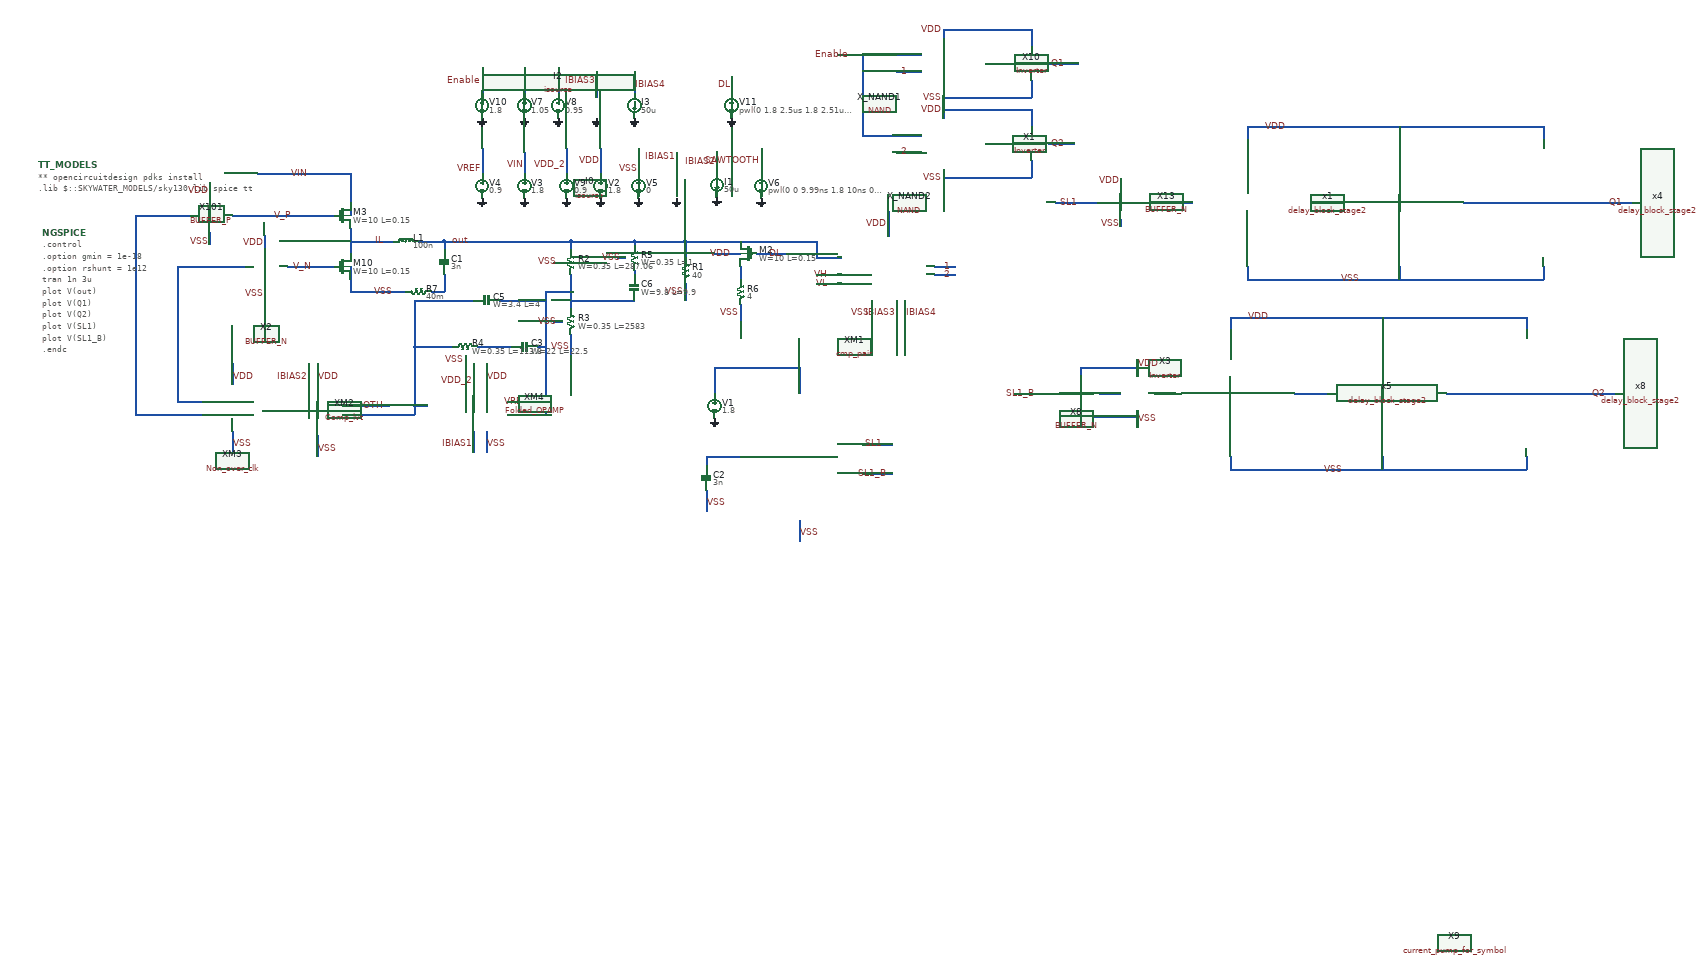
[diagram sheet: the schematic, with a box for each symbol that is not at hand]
v {xschem version=3.0.0 file_version=1.2 }
G {}
K {}
V {}
S {}
E {}
N 470 80 470 140 {
lab=IL}
N 470 20 470 50 {
lab=VIN}
N 380 50 430 50 {
lab=V_P}
N 470 -50 470 20 {
lab=VIN}
N 250 -50 470 -50 {
lab=VIN}
N 470 200 470 230 {
lab=VSS}
N 470 110 530 110 {
lab=IL}
N 530 110 570 110 {
lab=IL}
N 690 110 690 130 {
lab=out}
N 630 110 690 110 {
lab=out}
N 690 190 690 230 {
lab=#net1}
N 690 110 800 110 {
lab=out}
N 790 400 790 450 {
lab=VDD}
N 760 400 760 450 {
lab=VDD_2}
N 790 560 790 610 {
lab=VSS}
N 760 560 760 610 {
lab=IBIAS1}
N 840 520 890 520 {
lab=#net2}
N 840 490 890 490 {
lab=VREF}
N 880 -100 880 -50 {
lab=VIN}
N 980 -110 980 -50 {
lab=VDD_2}
N 1060 -60 1060 -50 {
lab=VDD}
N 1060 -110 1060 -60 {
lab=VDD}
N 1150 -80 1150 -60 {
lab=VSS}
N 1150 -60 1150 -50 {
lab=VSS}
N 1150 -110 1150 -80 {
lab=VSS}
N 1240 -100 1240 -40 {
lab=IBIAS1}
N 390 400 390 450 {
lab=VDD}
N 390 570 390 620 {
lab=VSS}
N 780 -80 780 -60 {
lab=VREF}
N 780 -60 780 -50 {
lab=VREF}
N 780 -110 780 -80 {
lab=VREF}
N 890 520 920 520 {
lab=#net2}
N 370 400 370 450 {
lab=IBIAS2}
N 1440 -110 1440 -50 {
lab=SAWTOOTH}
N 190 50 380 50 {
lab=V_P}
N 800 110 980 110 {
lab=out}
N 990 110 990 130 {
lab=out}
N 990 190 990 240 {
lab=#net2}
N 990 330 990 380 {
lab=VSS}
N 770 360 850 360 {
lab=#net3}
N 620 360 710 360 {
lab=#net4}
N 620 360 620 500 {
lab=#net4}
N 930 360 930 490 {
lab=#net2}
N 910 360 930 360 {
lab=#net2}
N 620 250 760 250 {
lab=#net4}
N 820 250 930 250 {
lab=#net2}
N 930 290 930 360 {
lab=#net2}
N 620 500 650 500 {
lab=#net4}
N 930 490 930 520 {
lab=#net2}
N 920 520 930 520 {
lab=#net2}
N 990 110 1140 110 {
lab=out}
N 1140 110 1140 120 {
lab=out}
N 1140 180 1140 190 {
lab=#net5}
N 980 110 990 110 {
lab=out}
N 930 230 930 290 {
lab=#net2}
N 930 230 990 230 {
lab=#net2}
N 990 240 990 270 {
lab=#net2}
N 1260 110 1260 150 {
lab=out}
N 1140 110 1260 110 {
lab=out}
N 1260 210 1260 250 {
lab=VSS}
N 450 520 620 520 {
lab=#net4}
N 620 500 620 520 {
lab=#net4}
N 380 170 430 170 {
lab=V_N}
N 470 170 470 200 {
lab=VSS}
N 1260 110 1390 110 {
lab=out}
N 1390 260 1390 300 {
lab=VSS}
N 1390 170 1390 200 {
lab=#net6}
N 1430 140 1500 140 {
lab=DL}
N 190 400 190 450 {
lab=VDD}
N 190 560 190 610 {
lab=VSS}
N -40 50 90 50 {
lab=#net7}
N -40 50 -40 490 {
lab=#net7}
N 135 90 135 117.5 {
lab=VSS}
N 135 -27.5 135 7.5 {
lab=VDD}
N 320 170 380 170 {
lab=V_N}
N 60 170 220 170 {
lab=#net8}
N 60 170 60 260 {
lab=#net8}
N 265 210 265 247.5 {
lab=VSS}
N 265 97.5 265 127.5 {
lab=VDD}
N 60 490 120 490 {
lab=#net8}
N 60 260 60 490 {
lab=#net8}
N -40 520 120 520 {
lab=#net7}
N -40 490 -40 520 {
lab=#net7}
N 620 250 620 360 {
lab=#net4}
N 990 250 1040 250 {
lab=#net2}
N 1040 250 1140 250 {
lab=#net2}
N 790 560 790 610 {
lab=VSS}
N 1330 140 1390 140 {
lab=VDD}
N 1335 -102.5 1335 -52.5 {
lab=IBIAS2}
N 270 510 320 510 {
lab=#net9}
N 450 500 560 500 {
lab=SAWTOOTH}
N 740 380 740 400 {
lab=VSS}
N 1100 150 1120 150 {
lab=VSS}
N 950 160 970 160 {
lab=VSS}
N 950 300 970 300 {
lab=VSS}
N 470 230 600 230 {
lab=VSS}
N 660 230 690 230 {
lab=#net1}
N 260 510 270 510 {
lab=#net9}
N 1850 170 1900 170 {
lab=1}
N 1850 190 1900 190 {
lab=2}
N 1780 250 1780 300 {
lab=IBIAS4}
N 1760 250 1760 310 {
lab=IBIAS3}
N 1700 250 1700 310 {
lab=VSS}
N 1740 40 1740 100 {
lab=VDD}
N 1570 150 1630 150 {
lab=out}
N 1570 190 1630 190 {
lab=VH}
N 1570 210 1630 210 {
lab=VL}
N 1570 110 1570 150 {
lab=out}
N 880 -300 880 -240 {
lab=VH}
N 960 -300 960 -240 {
lab=VL}
N 1050 -290 1050 -230 {
lab=IBIAS3}
N 1140 -290 1140 -240 {
lab=IBIAS4}
N 1680 -140 1820 -140 {
lab=Enable}
N 1680 -330 1820 -330 {
lab=Enable}
N 1620 -330 1680 -330 {
lab=Enable}
N 1760 -290 1820 -290 {
lab=1}
N 1760 -100 1820 -100 {
lab=2}
N 2120 -310 2180 -310 {
lab=Q1}
N 2120 -120 2180 -120 {
lab=Q2}
N 2180 -310 2190 -310 {
lab=Q1}
N 780 -300 780 -240 {
lab=Enable}
N 1370 -260 1370 -240 {
lab=DL}
N 1370 -280 1370 -260 {
lab=DL}
N 1390 110 1570 110 {
lab=out}
N 1870 -60 1870 -40 {
lab=VSS}
N 1870 -40 2010 -40 {
lab=VSS}
N 1870 -200 1870 -180 {
lab=VDD}
N 1870 -200 2010 -200 {
lab=VDD}
N 1870 -250 1870 -230 {
lab=VSS}
N 1870 -230 2010 -230 {
lab=VSS}
N 1870 -390 1870 -370 {
lab=VDD}
N 1680 -330 1680 -140 {
lab=Enable}
N 2240 470 2290 470 {
lab=#net10}
N 2330 510 2330 550 {
lab=VSS}
N 2330 390 2330 430 {
lab=VDD}
N 2040 470 2140 470 {
lab=SL1_B}
N 2195 410 2195 427.5 {
lab=VDD}
N 2195 410 2330 410 {
lab=VDD}
N 2195 510 2195 525 {
lab=VSS}
N 2195 525 2330 525 {
lab=VSS}
N 2135 20 2235 20 {
lab=SL1}
N 2290 -37.5 2290 -22.5 {
lab=VDD}
N 2290 60 2290 75 {
lab=VSS}
N 2010 -230 2080 -230 {
lab=VSS}
N 1880 -390 2080 -390 {
lab=VDD}
N 1870 -390 1880 -390 {
lab=VDD}
N 2010 -40 2080 -40 {
lab=VSS}
N 2010 -200 2080 -200 {
lab=VDD}
N 2080 -390 2080 -350 {
lab=VDD}
N 2080 -270 2080 -230 {
lab=VSS}
N 1970 -310 2040 -310 {
lab=#net11}
N 1970 -120 2040 -120 {
lab=#net12}
N 2080 -200 2080 -160 {
lab=VDD}
N 2080 -80 2080 -40 {
lab=VSS}
N 1530 770 1530 820 {
lab=VSS}
N 1530 770 1530 820 {
lab=VSS}
N 1330 420 1330 470 {
lab=#net13}
N 1530 410 1530 470 {
lab=#net13}
N 1330 410 1530 410 {
lab=#net13}
N 1330 410 1330 420 {
lab=#net13}
N 1310 620 1390 620 {
lab=#net14}
N 1310 620 1310 640 {
lab=#net14}
N 1310 700 1310 750 {
lab=VSS}
N 1310 700 1310 750 {
lab=VSS}
N 1680 590 1750 590 {
lab=SL1}
N 1680 660 1750 660 {
lab=SL1_B}
N 2740 20 2780 20 {
lab=#net15}
N 2780 20 2820 20 {
lab=#net15}
N 2590 -160 2590 -130 {
lab=VDD}
N 2950 -160 2950 -130 {
lab=VDD}
N 2950 170 2950 200 {
lab=VSS}
N 2590 170 2590 200 {
lab=VSS}
N 2700 470 2740 470 {
lab=#net16}
N 2740 470 2780 470 {
lab=#net16}
N 2550 290 2550 320 {
lab=VDD}
N 2910 290 2910 320 {
lab=VDD}
N 2910 620 2910 650 {
lab=VSS}
N 2550 620 2550 650 {
lab=VSS}
N 3060 470 3120 470 {
lab=#net17}
N 2370 470 2420 470 {
lab=#net18}
N 2335 20 2460 20 {
lab=#net19}
N 3120 20 3160 20 {
lab=#net20}
N 3290 -160 3290 -130 {
lab=VDD}
N 3290 170 3290 200 {
lab=VSS}
N 3440 20 3500 20 {
lab=Q1}
N 3250 290 3250 320 {
lab=VDD}
N 3250 620 3250 650 {
lab=VSS}
N 3400 470 3460 470 {
lab=Q2}
N 3100 20 3120 20 {
lab=#net20}
N 2550 650 3250 650 {
lab=VSS}
N 2550 290 3250 290 {
lab=VDD}
N 2590 200 3290 200 {
lab=VSS}
N 2590 -160 3290 -160 {
lab=VDD}
N 3120 470 3400 470 {}
N 3160 20 3440 20 {}
C {sky130_fd_pr/pfet_01v8.sym} 450 50 0 0 {name=M3
L=0.15
W=10
nf=1
mult=450
ad="'int((nf+1)/2) * W/nf * 0.29'" 
pd="'2*int((nf+1)/2) * (W/nf + 0.29)'"
as="'int((nf+2)/2) * W/nf * 0.29'" 
ps="'2*int((nf+2)/2) * (W/nf + 0.29)'"
nrd="'0.29 / W'" nrs="'0.29 / W'"
sa=0 sb=0 sd=0
model=pfet_01v8
spiceprefix=X
}
C {devices/ind.sym} 600 110 3 0 {name=L1
m=1
value=100n
footprint=1206
device=inductor}
C {devices/capa.sym} 690 160 0 0 {name=C1
m=1
value=3n
footprint=1206
device="ceramic capacitor"}
C {devices/code.sym} -270 -70 0 0 {name=TT_MODELS
only_toplevel=true
format="tcleval( @value )"
value="
** opencircuitdesign pdks install
.lib $::SKYWATER_MODELS/sky130.lib.spice tt

"
spice_ignore=false}
C {devices/code_shown.sym} -260 90 0 0 {name=NGSPICE
only_toplevel=true
value="

.control

.option gmin = 1e-18
.option rshunt = 1e12
tran 1n 3u
plot V(out)
plot V(Q1)
plot V(Q2) 
plot V(SL1)
plot V(SL1_B)
.endc
" }
C {devices/lab_wire.sym} 750 110 0 0 {name=l4 sig_type=std_logic lab=out}
C {devices/lab_wire.sym} 550 110 0 0 {name=l6 sig_type=std_logic lab=IL}
C {devices/lab_wire.sym} 370 -50 0 0 {name=l5 sig_type=std_logic lab=VIN}
C {devices/vsource.sym} 880 -20 0 0 {name=V3 value=1.8}
C {devices/gnd.sym} 880 10 0 0 {name=l7 lab=GND}
C {devices/lab_wire.sym} 880 -70 0 0 {name=l2 sig_type=std_logic lab=VIN}
C {devices/gnd.sym} 1240 10 0 0 {name=l19 lab=GND}
C {devices/lab_wire.sym} 1240 -90 0 0 {name=l22 sig_type=std_logic lab=IBIAS1}
C {devices/isource.sym} 1240 -20 0 0 {name=I0 value=50u}
C {devices/vsource.sym} 980 -20 0 0 {name=V9 value=0.9}
C {devices/gnd.sym} 980 10 0 0 {name=l42 lab=GND}
C {devices/lab_wire.sym} 980 -70 0 0 {name=l8 sig_type=std_logic lab=VDD_2}
C {devices/vsource.sym} 1060 -20 0 0 {name=V2 value=1.8}
C {devices/gnd.sym} 1060 10 0 0 {name=l18 lab=GND}
C {devices/vsource.sym} 1150 -20 0 0 {name=V5 value=0}
C {devices/gnd.sym} 1150 10 0 0 {name=l26 lab=GND}
C {devices/lab_wire.sym} 1150 -60 0 0 {name=l10 sig_type=std_logic lab=VSS}
C {devices/lab_wire.sym} 790 430 0 1 {name=l13 sig_type=std_logic lab=VDD}
C {devices/lab_wire.sym} 760 440 0 0 {name=l14 sig_type=std_logic lab=VDD_2}
C {devices/lab_wire.sym} 570 230 0 0 {name=l1 sig_type=std_logic lab=VSS}
C {devices/lab_wire.sym} 790 590 0 1 {name=l15 sig_type=std_logic lab=VSS}
C {devices/lab_wire.sym} 760 590 0 0 {name=l16 sig_type=std_logic lab=IBIAS1}
C {devices/lab_wire.sym} 390 430 0 1 {name=l11 sig_type=std_logic lab=VDD}
C {devices/lab_wire.sym} 390 600 0 1 {name=l12 sig_type=std_logic lab=VSS}
C {devices/vsource.sym} 780 -20 0 0 {name=V4 value=0.9}
C {devices/gnd.sym} 780 10 0 0 {name=l17 lab=GND}
C {devices/lab_wire.sym} 780 -60 0 0 {name=l20 sig_type=std_logic lab=VREF}
C {devices/isource.sym} 1335 -22.5 0 1 {name=I1 value=50u}
C {devices/lab_wire.sym} 370 430 0 0 {name=l27 sig_type=std_logic lab=IBIAS2}
C {devices/vsource.sym} 1440 -20 0 0 {name=V6 value="pwl(0 0 9.99ns 1.8 10ns 0) r=0"}
C {devices/gnd.sym} 1440 10 0 0 {name=l28 lab=GND}
C {devices/gnd.sym} 1440 10 0 0 {name=l29 lab=GND}
C {devices/lab_wire.sym} 1440 -80 0 0 {name=l30 sig_type=std_logic lab=SAWTOOTH}
C {devices/lab_wire.sym} 990 360 0 0 {name=l31 sig_type=std_logic lab=VSS}
C {devices/lab_wire.sym} 890 490 0 0 {name=l33 sig_type=std_logic lab=VREF}
C {devices/lab_wire.sym} 550 500 0 0 {name=l32 sig_type=std_logic lab=SAWTOOTH}
C {devices/lab_wire.sym} 1260 230 0 0 {name=l21 sig_type=std_logic lab=VSS}
C {sky130_fd_pr/pfet_01v8.sym} 1410 140 0 1 {name=M2
L=0.15
W=10
nf=1
mult=450
ad="'int((nf+1)/2) * W/nf * 0.29'" 
pd="'2*int((nf+1)/2) * (W/nf + 0.29)'"
as="'int((nf+2)/2) * W/nf * 0.29'" 
ps="'2*int((nf+2)/2) * (W/nf + 0.29)'"
nrd="'0.29 / W'" nrs="'0.29 / W'"
sa=0 sb=0 sd=0
model=pfet_01v8
spiceprefix=X
}
C {devices/lab_wire.sym} 1390 280 0 0 {name=l23 sig_type=std_logic lab=VSS}
C {devices/lab_wire.sym} 190 430 0 1 {name=l35 sig_type=std_logic lab=VDD}
C {devices/lab_wire.sym} 190 590 0 1 {name=l37 sig_type=std_logic lab=VSS}
C {DC_DC_Converter/BUFFER/BUFFER_PMOS/BUFFER_P.sym} 70 100 0 0 {name=X101}
C {devices/lab_wire.sym} 135 -10 0 0 {name=l38 sig_type=std_logic lab=VDD}
C {devices/lab_wire.sym} 135 112.5 0 0 {name=l40 sig_type=std_logic lab=VSS}
C {DC_DC_Converter/BUFFER/BUFFER_NMOS/BUFFER_N.sym} 130 250 0 0 {name=X2}
C {devices/lab_wire.sym} 265 235 0 0 {name=l39 sig_type=std_logic lab=VSS}
C {devices/lab_wire.sym} 265 115 0 0 {name=l41 sig_type=std_logic lab=VDD}
C {DC_DC_Converter/Non_Overlap_Clk/Non_over_clk.sym} 390 770 0 1 {name=XM3}
C {devices/lab_wire.sym} 330 50 0 0 {name=l3 sig_type=std_logic lab=V_P}
C {devices/lab_wire.sym} 380 170 0 0 {name=l43 sig_type=std_logic lab=V_N}
C {DC_DC_Converter/Folded_OPAMP/Folded_OPAMP.sym} 850 560 0 1 {name=XM4}
C {devices/lab_wire.sym} 1490 140 0 0 {name=l96 sig_type=std_logic lab=DL}
C {sky130_fd_pr/cap_mim_m3_1.sym} 790 250 3 0 {name=C5 model=cap_mim_m3_1 W=3.4 L=4 MF=1 spiceprefix=X}
C {sky130_fd_pr/cap_mim_m3_1.sym} 880 360 3 0 {name=C3 model=cap_mim_m3_1 W=22 L=22.5 MF=1 spiceprefix=X}
C {sky130_fd_pr/cap_mim_m3_1.sym} 1140 220 0 0 {name=C6 model=cap_mim_m3_1 W=9.8 L=9.9 MF=1 spiceprefix=X}
C {devices/lab_wire.sym} 1060 -80 0 0 {name=l97 sig_type=std_logic lab=VDD}
C {devices/lab_wire.sym} 1370 140 0 0 {name=l98 sig_type=std_logic lab=VDD}
C {sky130_fd_pr/nfet_01v8.sym} 450 170 0 0 {name=M10
L=0.15
W=10
nf=1 
mult=150
ad="'int((nf+1)/2) * W/nf * 0.29'" 
pd="'2*int((nf+1)/2) * (W/nf + 0.29)'"
as="'int((nf+2)/2) * W/nf * 0.29'" 
ps="'2*int((nf+2)/2) * (W/nf + 0.29)'"
nrd="'0.29 / W'" nrs="'0.29 / W'"
sa=0 sb=0 sd=0
model=nfet_01v8
spiceprefix=X
}
C {devices/lab_wire.sym} 1335 -77.5 0 0 {name=l24 sig_type=std_logic lab=IBIAS2}
C {sky130_fd_pr/res_high_po_0p35.sym} 740 360 3 0 {name=R4
W=0.35
L=113.8
model=res_high_po_0p35
spiceprefix=X
mult=1}
C {devices/lab_wire.sym} 740 390 3 0 {name=l9 sig_type=std_logic lab=VSS}
C {sky130_fd_pr/res_high_po_0p35.sym} 1140 150 0 0 {name=R5
W=0.35
L=1
model=res_high_po_0p35
spiceprefix=X
mult=1}
C {devices/lab_wire.sym} 1110 150 0 0 {name=l44 sig_type=std_logic lab=VSS}
C {sky130_fd_pr/res_high_po_0p35.sym} 990 160 0 0 {name=R2
W=0.35
L=287.06
model=res_high_po_0p35
spiceprefix=X
mult=1}
C {devices/lab_wire.sym} 960 160 0 0 {name=l45 sig_type=std_logic lab=VSS}
C {sky130_fd_pr/res_high_po_0p35.sym} 990 300 0 0 {name=R3
W=0.35
L=2583
model=res_high_po_0p35
spiceprefix=X
mult=1}
C {devices/lab_wire.sym} 960 300 0 0 {name=l46 sig_type=std_logic lab=VSS}
C {devices/res.sym} 630 230 1 0 {name=R7
value=40m
footprint=1206
device=resistor
m=1}
C {devices/res.sym} 1260 180 0 0 {name=R1
value=40
footprint=1206
device=resistor
m=1}
C {devices/res.sym} 1390 230 0 0 {name=R6
value=4
footprint=1206
device=resistor
m=1}
C {DC_DC_Converter/Comparator/Comp_lvt.sym} 470 580 0 1 {name=XM2}
C {devices/lab_wire.sym} 1780 280 0 1 {name=l48 sig_type=std_logic lab=IBIAS4}
C {devices/lab_wire.sym} 1760 280 0 0 {name=l49 sig_type=std_logic lab=IBIAS3}
C {devices/lab_pin.sym} 1700 280 0 0 {name=l50 sig_type=std_logic lab=VSS}
C {devices/lab_pin.sym} 1740 70 0 0 {name=l51 sig_type=std_logic lab=VDD}
C {devices/lab_pin.sym} 1600 190 1 0 {name=l53 sig_type=std_logic lab=VH}
C {devices/lab_pin.sym} 1600 210 3 0 {name=l54 sig_type=std_logic lab=VL}
C {DC_DC_Converter/Comparator_Pair/cmp_pair.sym} 1610 250 0 0 {name=XM1}
C {devices/lab_wire.sym} 1890 170 0 0 {name=l47 sig_type=std_logic lab=1}
C {devices/lab_wire.sym} 1890 190 0 0 {name=l87 sig_type=std_logic lab=2}
C {devices/vsource.sym} 880 -210 0 0 {name=V7 value=1.05}
C {devices/gnd.sym} 880 -180 0 0 {name=l52 lab=GND}
C {devices/lab_pin.sym} 880 -270 0 0 {name=l55 sig_type=std_logic lab=VH}
C {devices/vsource.sym} 960 -210 0 0 {name=V8 value=0.95}
C {devices/gnd.sym} 960 -180 0 0 {name=l56 lab=GND}
C {devices/lab_pin.sym} 960 -270 0 0 {name=l57 sig_type=std_logic lab=VL}
C {devices/gnd.sym} 1050 -180 0 0 {name=l58 lab=GND}
C {devices/isource.sym} 1050 -210 0 0 {name=I2 value=50u}
C {devices/isource.sym} 1140 -210 0 0 {name=I3 value=50u}
C {devices/gnd.sym} 1140 -180 0 0 {name=l60 lab=GND}
C {devices/lab_wire.sym} 1050 -270 0 0 {name=l59 sig_type=std_logic lab=IBIAS3}
C {devices/lab_wire.sym} 1140 -260 0 1 {name=l61 sig_type=std_logic lab=IBIAS4}
C {devices/noconn.sym} 1900 190 0 1 {name=l62}
C {devices/noconn.sym} 1900 170 0 1 {name=l63}
C {DC_DC_Converter/NAND_GATE/NAND.sym} 1800 -240 0 0 {name=X_NAND1}
C {DC_DC_Converter/NAND_GATE/NAND.sym} 1800 -50 0 0 {name=X_NAND2}
C {devices/lab_pin.sym} 1870 -40 0 0 {name=l84 sig_type=std_logic lab=VSS}
C {devices/lab_wire.sym} 2160 -120 0 0 {name=l86 sig_type=std_logic lab=Q2}
C {devices/lab_wire.sym} 1790 -290 0 0 {name=l64 sig_type=std_logic lab=1}
C {devices/lab_wire.sym} 1790 -100 0 0 {name=l88 sig_type=std_logic lab=2}
C {devices/lab_wire.sym} 1650 -330 0 0 {name=l91 sig_type=std_logic lab=Enable}
C {devices/lab_pin.sym} 1870 -200 0 0 {name=l94 sig_type=std_logic lab=VDD}
C {devices/lab_wire.sym} 2160 -310 0 0 {name=l79 sig_type=std_logic lab=Q1}
C {devices/gnd.sym} 780 -180 0 0 {name=l89 lab=GND}
C {devices/lab_pin.sym} 780 -270 0 0 {name=l90 sig_type=std_logic lab=Enable}
C {devices/vsource.sym} 780 -210 0 0 {name=V10 value=1.8}
C {devices/gnd.sym} 1335 7.5 0 0 {name=l25 lab=GND}
C {devices/vsource.sym} 1370 -210 0 0 {name=V11 value="pwl(0 1.8 2.5us 1.8 2.51us 0 5us 0) r=0"}
C {devices/gnd.sym} 1370 -180 0 0 {name=l65 lab=GND}
C {devices/gnd.sym} 1370 -180 0 0 {name=l66 lab=GND}
C {devices/lab_wire.sym} 1370 -260 0 0 {name=l67 sig_type=std_logic lab=DL}
C {devices/lab_pin.sym} 1870 -230 0 0 {name=l34 sig_type=std_logic lab=VSS}
C {devices/lab_pin.sym} 1870 -390 0 0 {name=l36 sig_type=std_logic lab=VDD}
C {devices/lab_wire.sym} 2190 20 0 0 {name=l71 sig_type=std_logic lab=SL1}
C {devices/lab_wire.sym} 2090 470 0 0 {name=l77 sig_type=std_logic lab=SL1_B}
C {DC_DC_Converter/Inverter/Inverter.sym} 2400 490 0 1 {name=X3}
C {devices/lab_pin.sym} 2330 400 0 1 {name=l81 sig_type=std_logic lab=VDD}
C {devices/lab_pin.sym} 2330 530 0 1 {name=l85 sig_type=std_logic lab=VSS}
C {DC_DC_Converter/BUFFER/BUFFER_NMOS/BUFFER_N.sym} 2330 550 0 1 {name=X8}
C {DC_DC_Converter/BUFFER/BUFFER_NMOS/BUFFER_N.sym} 2425 100 0 1 {name=X13}
C {devices/lab_pin.sym} 2290 70 0 0 {name=l114 sig_type=std_logic lab=VSS}
C {devices/lab_pin.sym} 2290 -32.5 0 0 {name=l115 sig_type=std_logic lab=VDD}
C {DC_DC_Converter/Inverter/Inverter.sym} 2010 -290 0 0 {name=X10}
C {DC_DC_Converter/Inverter/Inverter.sym} 2010 -100 0 0 {name=X1}
C {DC_DC_Converter/current_pump/current_pump_for_symbol.sym} 3080 1770 0 1 {name=X9}
C {devices/lab_wire.sym} 1530 800 0 1 {name=l103 sig_type=std_logic lab=VSS}
C {devices/vsource.sym} 1330 500 0 0 {name=V1 value=1.8}
C {devices/gnd.sym} 1330 530 0 0 {name=l104 lab=GND}
C {devices/capa.sym} 1310 670 0 0 {name=C2
m=1
value=3n
footprint=1206
device="ceramic capacitor"}
C {devices/lab_wire.sym} 1310 730 0 1 {name=l106 sig_type=std_logic lab=VSS}
C {devices/lab_wire.sym} 1730 590 0 0 {name=l107 sig_type=std_logic lab=SL1}
C {devices/lab_wire.sym} 1740 660 0 0 {name=l108 sig_type=std_logic lab=SL1_B}
C {DC_DC_Converter/Delay_block_revised/delay_block_stage2.sym} 3050 40 0 1 {name=x1}
C {DC_DC_Converter/Delay_block_revised/delay_block_stage2.sym} 3410 40 0 1 {name=x4}
C {devices/lab_pin.sym} 2682.5 -160 1 0 {name=l68 sig_type=std_logic lab=VDD}
C {devices/lab_pin.sym} 2857.5 200 3 0 {name=l69 sig_type=std_logic lab=VSS}
C {DC_DC_Converter/Delay_block_revised/delay_block_stage2.sym} 3010 490 0 1 {name=x5}
C {DC_DC_Converter/Delay_block_revised/delay_block_stage2.sym} 3370 490 0 1 {name=x8}
C {devices/lab_pin.sym} 2642.5 290 1 0 {name=l72 sig_type=std_logic lab=VDD}
C {devices/lab_pin.sym} 2817.5 650 3 0 {name=l73 sig_type=std_logic lab=VSS}
C {devices/lab_wire.sym} 3480 20 0 0 {name=l76 sig_type=std_logic lab=Q1}
C {devices/lab_wire.sym} 3440 470 0 0 {name=l80 sig_type=std_logic lab=Q2}
